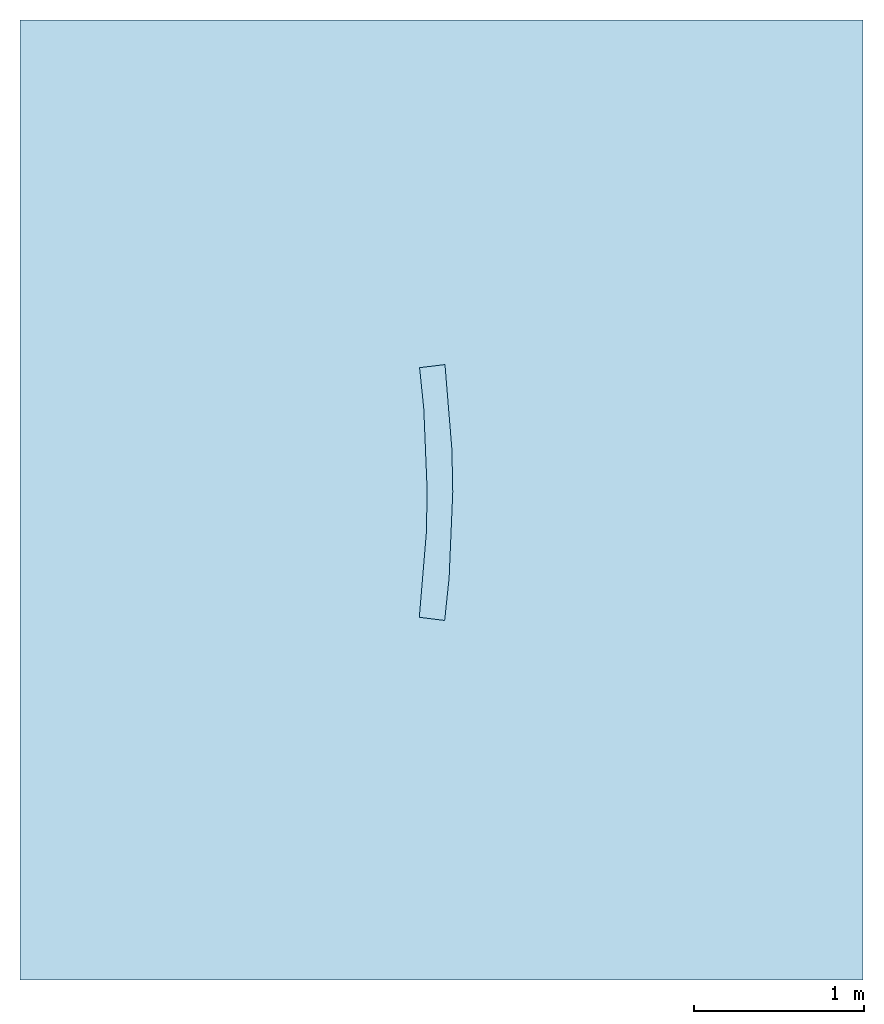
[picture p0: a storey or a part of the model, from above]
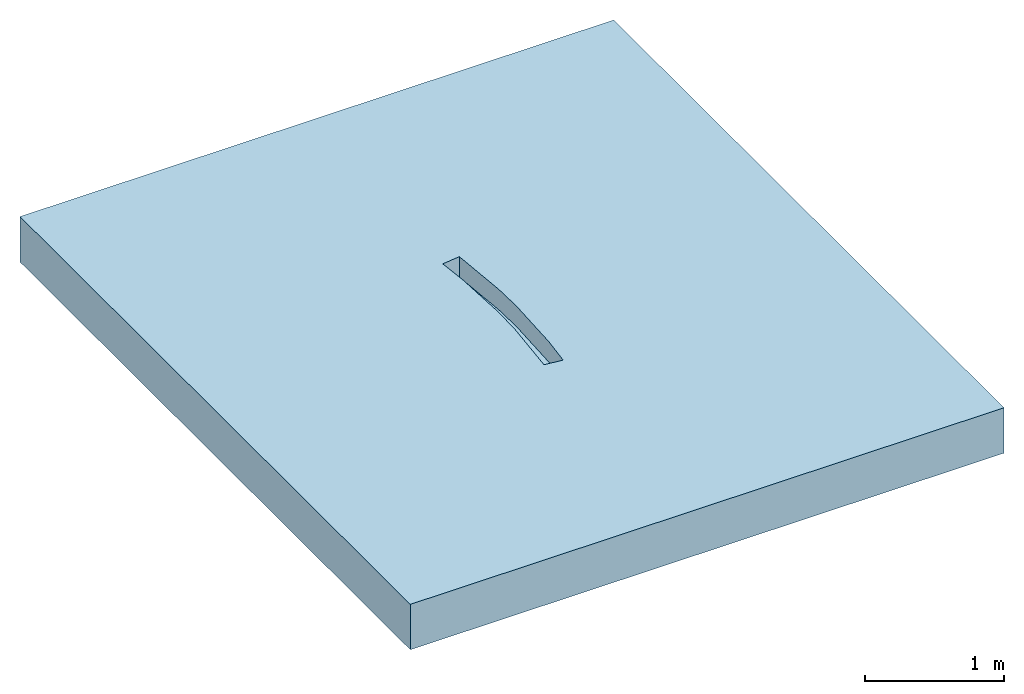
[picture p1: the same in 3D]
Properties of the parts of a building model (IFC2X3)

# File
Description: ViewDefinition [CoordinationView]
File name: 4998 - LH drop kerb_6m external radius.ifc
Time: 2013-09-12T12:54:56
Written by: Autodesk Revit 2013
Made in: 20120221_2030(x64)

# IfcProject, Project Number
LongName: Project Name; Phase: Project Status

# IfcSite, Default
RefLatitude: 42, 21, 30, 344238; RefLongitude: -71, -3, -35, -194702; RefElevation: 0 mm

# IfcBuilding
Pset_BuildingCommon - NumberOfStoreys: 2
Other - Client Name: Owner; Project Number: Project Number; Project Name: Project Name; Project Status: Project Status; Project Address: Enter address here; Project Issue Date: Issue Date

# IfcBuildingStorey (2)
Constraints - Elevation Base: 0
Graphics - Symbol at End 2 Default: yes; Line Pattern: Center; Line Weight: 1; Symbol at End 1 Default: no; Symbol: M_Level Head - Circle: M_Level Head - Circle; Color: 0
Identity Data - Building Story: yes; Structural: no
Dimensions - Computation Height: 0 mm
Name | LongName = Name | Elevation (mm) = Constraints, Elevation (mm)
T.O. Fnd. Wall | T.O. Fnd. Wall | -300
Level 1 | Level 1 | 0

# IfcBuildingElementProxy: 4998 - LH drop kerb_6m external radius, Civil-Drainage-Channel-ACO-KerbDrain-HB305 Part 2:4998 - LH drop kerb_6m external radius:4998 - LH drop kerb_6m external radius:263456
In: T.O. Fnd. Wall
Material: ACO Polymer Concrete.
Other - CreatedBy: www.aco.co.uk; Revision: 1
Materials and Finishes - Connection Pipe Material: N/A; End Cap Colour: N/A; Connection Pipe Material Colour: N/A; Channel Material: Vienite® Synthetic Resin Concrete; End Cap Material: N/A; Channel Colour: Grey; Access Cover/Frame Colour: N/A; Access Cover/Frame Material: N/A; Access Cover/Frame Finish: N/A
Dimensions - Mite Long Side Length: 497 mm; Void_Width: 150 mm; Quadrant void Start: 2600.7 mm; Mitre Void Start: -6150 mm; mitre small length: 484 mm; Straight Void Depth: -5200 mm; Mitre Void End: -6155 mm; Flush Drainable Centre Stone Void Start: -4500 mm; Void L Start: -3000 mm; Void_Length: 500 mm; 1.8m Radius Unit void End: -4805 mm; 1.8m Radius unit Void Start: -4800 mm; Flush Drainable Centre Stone Void End: -4505 mm; Curved RH Void End: -3070 mm; Curved LH Void End: 180 mm; Staright Void Depth: -5205 mm; 6m Radius Unit Void end: -6005 mm; Curved RH Void Start: -3060 mm; Void L End: -3010 mm; Quadrant void End: 2620 mm; Curved LH Void Start: 0 mm; 6m Radius unit void Start: -6000 mm; Volume: 34177385 mm3
Phasing - Phase Created: Phase 1
Constraints - Moves With Nearby Elements: no; Level: Level: Level 1
Pset_BuildingElementProxyCommon - Reference: 4998 - LH drop kerb_6m external radius
Construction - KDHB305 25-11m internal_mitre: no; KDHB305 25-11m external_mitre: no; KDHB305 internal_angle: no; KDHB305 RH drop kerb-4999: no; KDHB305 10-8m_external_mitre: no; KDHB305_quadrant: no; KDHB305 7-6m external_mitre: no; KDHB305 6m _external_radius: no; LH drop kerb- 6m ext rad: yes; KDHB305 1.8m_radius: no; flush drainable centre stone: no
General - TagNumber: 0.000000; SerialNumber: 0.000000
Identity Data - e-mail Technical: technical@aco.co.uk; Price: POA - contact ACO; Model Description: Combined kerb and drainage system; OmniClass Number: 23.70.50.24; Product Code: 4998; OmniClass Title: Rainwater Removal; Product brochure: http://www.aco.co.uk/download.php?id=120; Maintenance guidelines: http://www.aco.co.uk/download.php?id=120; Fax: +44 (0)1462 815895; Assembly Description: Rain Water Drainage; e-mail Sales: customersupport@aco.co.uk; Assembly Code: D2040; Product Page URL: http://www.aco.co.uk/product_detail.php?id=3; Model: ACO KerbDrain HB305; Address: ACO Business Park, Hitchin Road, Shefford, Bedfordshire, United Kingdom SG17 5TE; Manufacturer: ACO Technologies plc - ACO Water Management Division; Type Comments: ACO KerbDrain HB305 half battered left-hand drop kerb assembly 6m external radius 1500mm long; URL: www.aco.co.uk; Cost: 0; Installation guidelines: http://www.aco.co.uk/download.php?id=120; Telephone: +44 (0)1462 816666
Green Building Properties - End Cap Recyclable: N/A; Channel Recyclable: Fully recyclable; Channel Recycled Material Content: 20% minimum; End Cap Recycled Material Content: N/A; Access Cover/Frame Recycled Material Content: N/A; Access Cover/Frame Recyclable: N/A
Data - Installation - Concrete Grade: Refer to brochure; Channel C.S.A: 0.02 to 0.008mm²; Product Standard: BS EN 1433:2002, CE marked, Kitemarked; Drainage Slot Intake area: N/A; Concrete Surround Volume - Load Class A 15 - D 400 - Concrete Pavement: N/A; Product Dimensions: 1500mm x 150mm x 180mm (LxWxH); Concrete Surround Volume - Load Class A 15 - D 400 - Grass or Asphalt Pavement: N/A; Load Class: A 15 - D 400; Product Weight: 77.5 Kg; Hydraulic Performance: http://www.aco.co.uk/download.php?id=120; ACO Hydraulic Design Software: http://www.acodesign.co.uk; Drainage Slot Width: N/A; Connection Pipe O.D: N/A; Invert Depth: 155mm

# IfcOpeningElement: Recess (9)
In: Level 1
Constraints - Related to Mass: no; Level: Level: Level 1; Room Bounding: yes; Height Offset From Level: 0 mm
Dimensions - Thickness: 400 mm; Volume: 11103432884 mm3; Perimeter: 21157.2 mm; Area: 27858925 mm2
Structural - Structural: no; Enable Analytical Model: no
Phasing - Phase Created: Phase 1
Analytical Properties - Roughness: 1; Absorptance: 0.1
Graphics - Coarse Scale Fill Color: 0
Construction - Function: 0; Default Thickness: 400 mm

# IfcSlab: Floor:Generic Floor - 400mm, Floor:Generic Floor - 400mm:184025
In: Level 1
PredefinedType: FLOOR; Material: Default Floor 400 mm
Constraints - Related to Mass: no; Level: Level: Level 1; Room Bounding: yes; Height Offset From Level: 0 mm
Dimensions - Thickness: 400 mm; Volume: 11103432884 mm3; Perimeter: 21157.2 mm; Area: 27858925 mm2
Structural - Structural: no; Enable Analytical Model: no
Phasing - Phase Created: Phase 1
Pset_SlabCommon - Reference: Generic Floor - 400mm; IsExternal: no; LoadBearing: yes
Analytical Properties - Roughness: 1; Absorptance: 0.1
Graphics - Coarse Scale Fill Color: 0
Construction - Function: 0; Default Thickness: 400 mm
